VERSION 5.8 ;
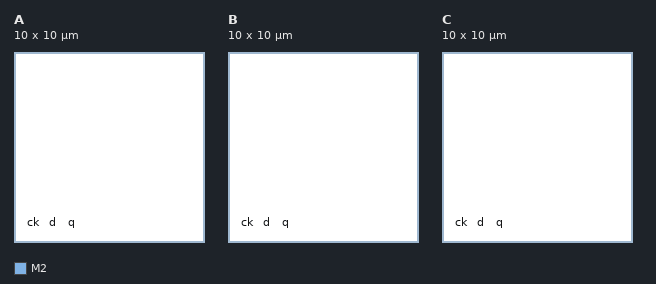
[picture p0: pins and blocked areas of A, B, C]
MACRO A
 CLASS BLOCK ;
 ORIGIN 0 0 ;
 SIZE 10 BY 10 ;
 PIN ck
 DIRECTION INPUT ;
 USE SIGNAL ;
 PORT
 LAYER M2 ;
 RECT 1 1 1.1 1.1 ;
 END
 END ck
 PIN d
 DIRECTION INPUT ;
 USE SIGNAL ;
 PORT
 LAYER M2 ;
 RECT 2 1 2.1 1.1 ;
 END
 END d
 PIN q
 DIRECTION OUTPUT ;
 USE SIGNAL ;
 PORT
 LAYER M2 ;
 RECT 3 1 3.1 1.1 ;
 END
 END q
END A
MACRO B
 CLASS BLOCK ;
 ORIGIN 0 0 ;
 SIZE 10 BY 10 ;
 PIN ck
 DIRECTION INPUT ;
 USE SIGNAL ;
 PORT
 LAYER M2 ;
 RECT 1 1 1.1 1.1 ;
 END
 END ck
 PIN d
 DIRECTION INPUT ;
 USE SIGNAL ;
 PORT
 LAYER M2 ;
 RECT 2 1 2.1 1.1 ;
 END
 END d
 PIN q
 DIRECTION OUTPUT ;
 USE SIGNAL ;
 PORT
 LAYER M2 ;
 RECT 3 1 3.1 1.1 ;
 END
 END q
END B
MACRO C
 CLASS BLOCK ;
 ORIGIN 0 0 ;
 SIZE 10 BY 10 ;
 PIN ck
 DIRECTION INPUT ;
 USE SIGNAL ;
 PORT
 LAYER M2 ;
 RECT 1 1 1.1 1.1 ;
 END
 END ck
 PIN d
 DIRECTION INPUT ;
 USE SIGNAL ;
 PORT
 LAYER M2 ;
 RECT 2 1 2.1 1.1 ;
 END
 END d
 PIN q
 DIRECTION OUTPUT ;
 USE SIGNAL ;
 PORT
 LAYER M2 ;
 RECT 3 1 3.1 1.1 ;
 END
 END q
END C
END LIBRARY
